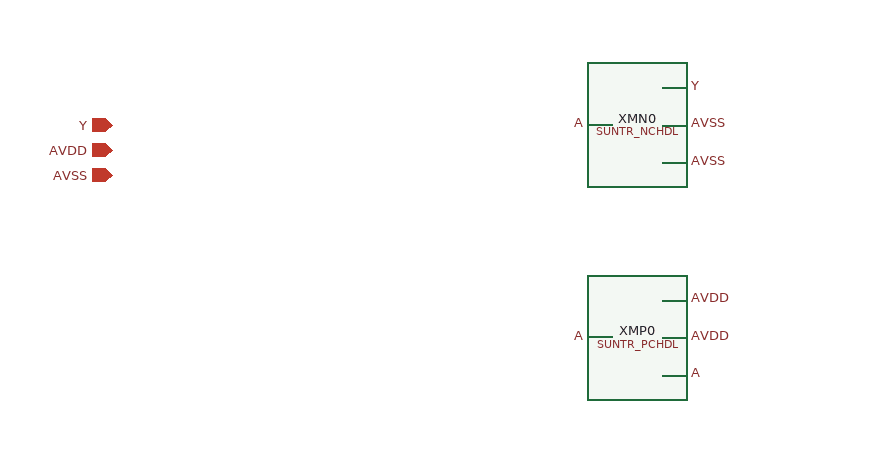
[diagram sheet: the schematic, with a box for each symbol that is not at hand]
v {xschem version=3.0.0 file_version=1.2 }
G {}
K {}
V {}
S {}
E {}
C {devices/iopin.sym} 0 0 0 0{name=p0 lab=Y}
C {devices/iopin.sym} 0 20 0 0{name=p1 lab=AVDD}
C {devices/iopin.sym} 0 40 0 0{name=p2 lab=AVSS}
C {SUN_TR_SKY130NM/SUNTR_NCHDL.sym} 400 0 0 0 {name=XMN0}
N 460.0 -30.0 440.0 -30.0{lab=Y}
C {devices/lab_pin.sym} 460.0 -30.0 2 0  {name=l0 sig_type=std_logic lab=Y }
N 380.0 0.0 400.0 0.0{lab=A}
C {devices/lab_pin.sym} 380.0 0.0 0 0  {name=l1 sig_type=std_logic lab=A }
N 460.0 30.0 440.0 30.0{lab=AVSS}
C {devices/lab_pin.sym} 460.0 30.0 2 0  {name=l2 sig_type=std_logic lab=AVSS }
N 460.0 0.0 440.0 0.0{lab=AVSS}
C {devices/lab_pin.sym} 460.0 0.0 2 0  {name=l3 sig_type=std_logic lab=AVSS }
C {SUN_TR_SKY130NM/SUNTR_PCHDL.sym} 400 170.0 0 0 {name=XMP0}
N 460.0 200.0 440.0 200.0{lab=A}
C {devices/lab_pin.sym} 460.0 200.0 2 0  {name=l4 sig_type=std_logic lab=A }
N 380.0 170.0 400.0 170.0{lab=A}
C {devices/lab_pin.sym} 380.0 170.0 0 0  {name=l5 sig_type=std_logic lab=A }
N 460.0 140.0 440.0 140.0{lab=AVDD}
C {devices/lab_pin.sym} 460.0 140.0 2 0  {name=l6 sig_type=std_logic lab=AVDD }
N 460.0 170.0 440.0 170.0{lab=AVDD}
C {devices/lab_pin.sym} 460.0 170.0 2 0  {name=l7 sig_type=std_logic lab=AVDD }
